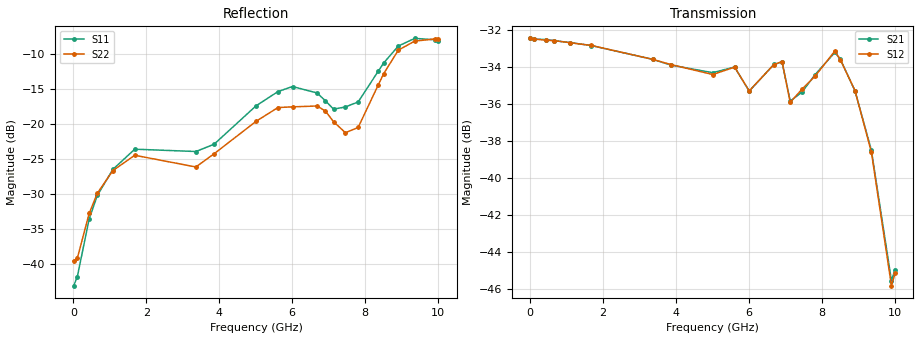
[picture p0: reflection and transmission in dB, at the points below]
! Device ID: PE43705
! Serial: 1
! Insertion: A
! Impedance: 50 ohm
! Temp: 25C
! VDD: 3.400V
! Attenuation Step: 31.50dB
#  Hz  S  RI  R  50
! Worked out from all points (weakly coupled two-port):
!   401 points, 10 MHz to 10.01 GHz, reference 50 ohm
!   highest |S21| = -32.49 dB at 10 MHz (marker M1); lowest = -45.6 dB at 9.91 GHz (marker M2)
!   lowest |S11| = -43.1 dB at 10 MHz (marker M3), VSWR 1.01, Z = 49.3 + j0.0419 ohm
!   |S11| at or under -10 dB: start of sweep to 8.693 GHz
!   |S22| runs from -39.7 to -7.8 dB; largest |S21 - S12| = 0.00057
!   S11 on the Smith chart (normalised r, x): 10 MHz: 0.99, +0.00; 7.46 GHz: 0.82, +0.16; 8.51 GHz: 0.82, +0.48; 9.36 GHz: 0.54, +0.48; 10.01 GHz: 0.48, +0.26
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1e7  -0.00699 0.000425  0.0238 -4.68e-05  0.0238 -0.000104  -0.0105 0.000568
1.1e8  -0.00665 0.00465  0.0237 -0.000643  0.0237 -0.000609  -0.0097 0.00516
4.35e8  -0.0118 0.0174  0.0235 -0.00237  0.0234 -0.00236  -0.0137 0.0185
6.6e8  -0.02 0.0236  0.0232 -0.00351  0.0232 -0.00352  -0.0202 0.0249
1.085e9  -0.0395 0.0262  0.0225 -0.00562  0.0225 -0.00556  -0.0365 0.0288
1.685e9  -0.064 0.0164  0.0212 -0.00827  0.0212 -0.00831  -0.0553 0.0227
3.36e9  -0.0635 0.00318  0.0156 -0.0139  0.0156 -0.0139  -0.0467 0.0158
3.86e9  -0.0668 0.026  0.0139 -0.0146  0.014 -0.0146  -0.0542 0.0286
5.01e9  -0.1035 0.0863  0.0111 -0.0157  0.011 -0.0155  -0.0866 0.0583
5.61e9  -0.1367 0.1015  0.00894 -0.0178  0.00889 -0.0178  -0.1122 0.0677
6.01e9  -0.1557 0.1001  0.00772 -0.0153  0.00779 -0.0153  -0.1157 0.0645
6.685e9  -0.1464 0.079  0.00695 -0.019  0.0069 -0.019  -0.1238 0.0523
6.91e9  -0.1285 0.0704  0.00379 -0.0202  0.00405 -0.0202  -0.1135 0.0493
7.135e9  -0.1157 0.0537  0.00314 -0.0158  0.00299 -0.0157  -0.0915 0.049
7.46e9  -0.093 0.0941  0.00385 -0.0166  0.00399 -0.0169  -0.0648 0.0574
7.81e9  -0.0486 0.1352  0.00416 -0.0185  0.00422 -0.0183  -0.0429 0.0842
8.36e9  -0.0166 0.2375  -0.00308 -0.0216  -0.00304 -0.0218  -0.0361 0.1865
8.51e9  -0.0255 0.2716  -0.00566 -0.0201  -0.00549 -0.0201  -0.0473 0.2239
8.91e9  -0.0806 0.3508  -0.00921 -0.0145  -0.00909 -0.0146  -0.114 0.3167
9.36e9  -0.1813 0.3661  -0.00812 -0.00866  -0.00795 -0.00863  -0.2135 0.3269
9.91e9  -0.3013 0.262  -0.00106 -0.00517  -0.00106 -0.005  -0.3501 0.2024
1.001e10  -0.3148 0.2275  0.000372 -0.00564  0.000103 -0.00552  -0.3671 0.1635
